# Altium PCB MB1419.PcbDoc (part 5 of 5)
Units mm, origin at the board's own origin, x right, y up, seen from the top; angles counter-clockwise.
Board outline 31 x 41 mm, 8 copper layers (Top Layer, Signal Layer 1, Signal Layer 2, Signal Layer 3, Signal Layer 4, Signal Layer 5, Signal Layer 6, Bottom Layer), stack 1.536 mm thick; 212 components, 125 nets, 637 pads, 2170 vias.

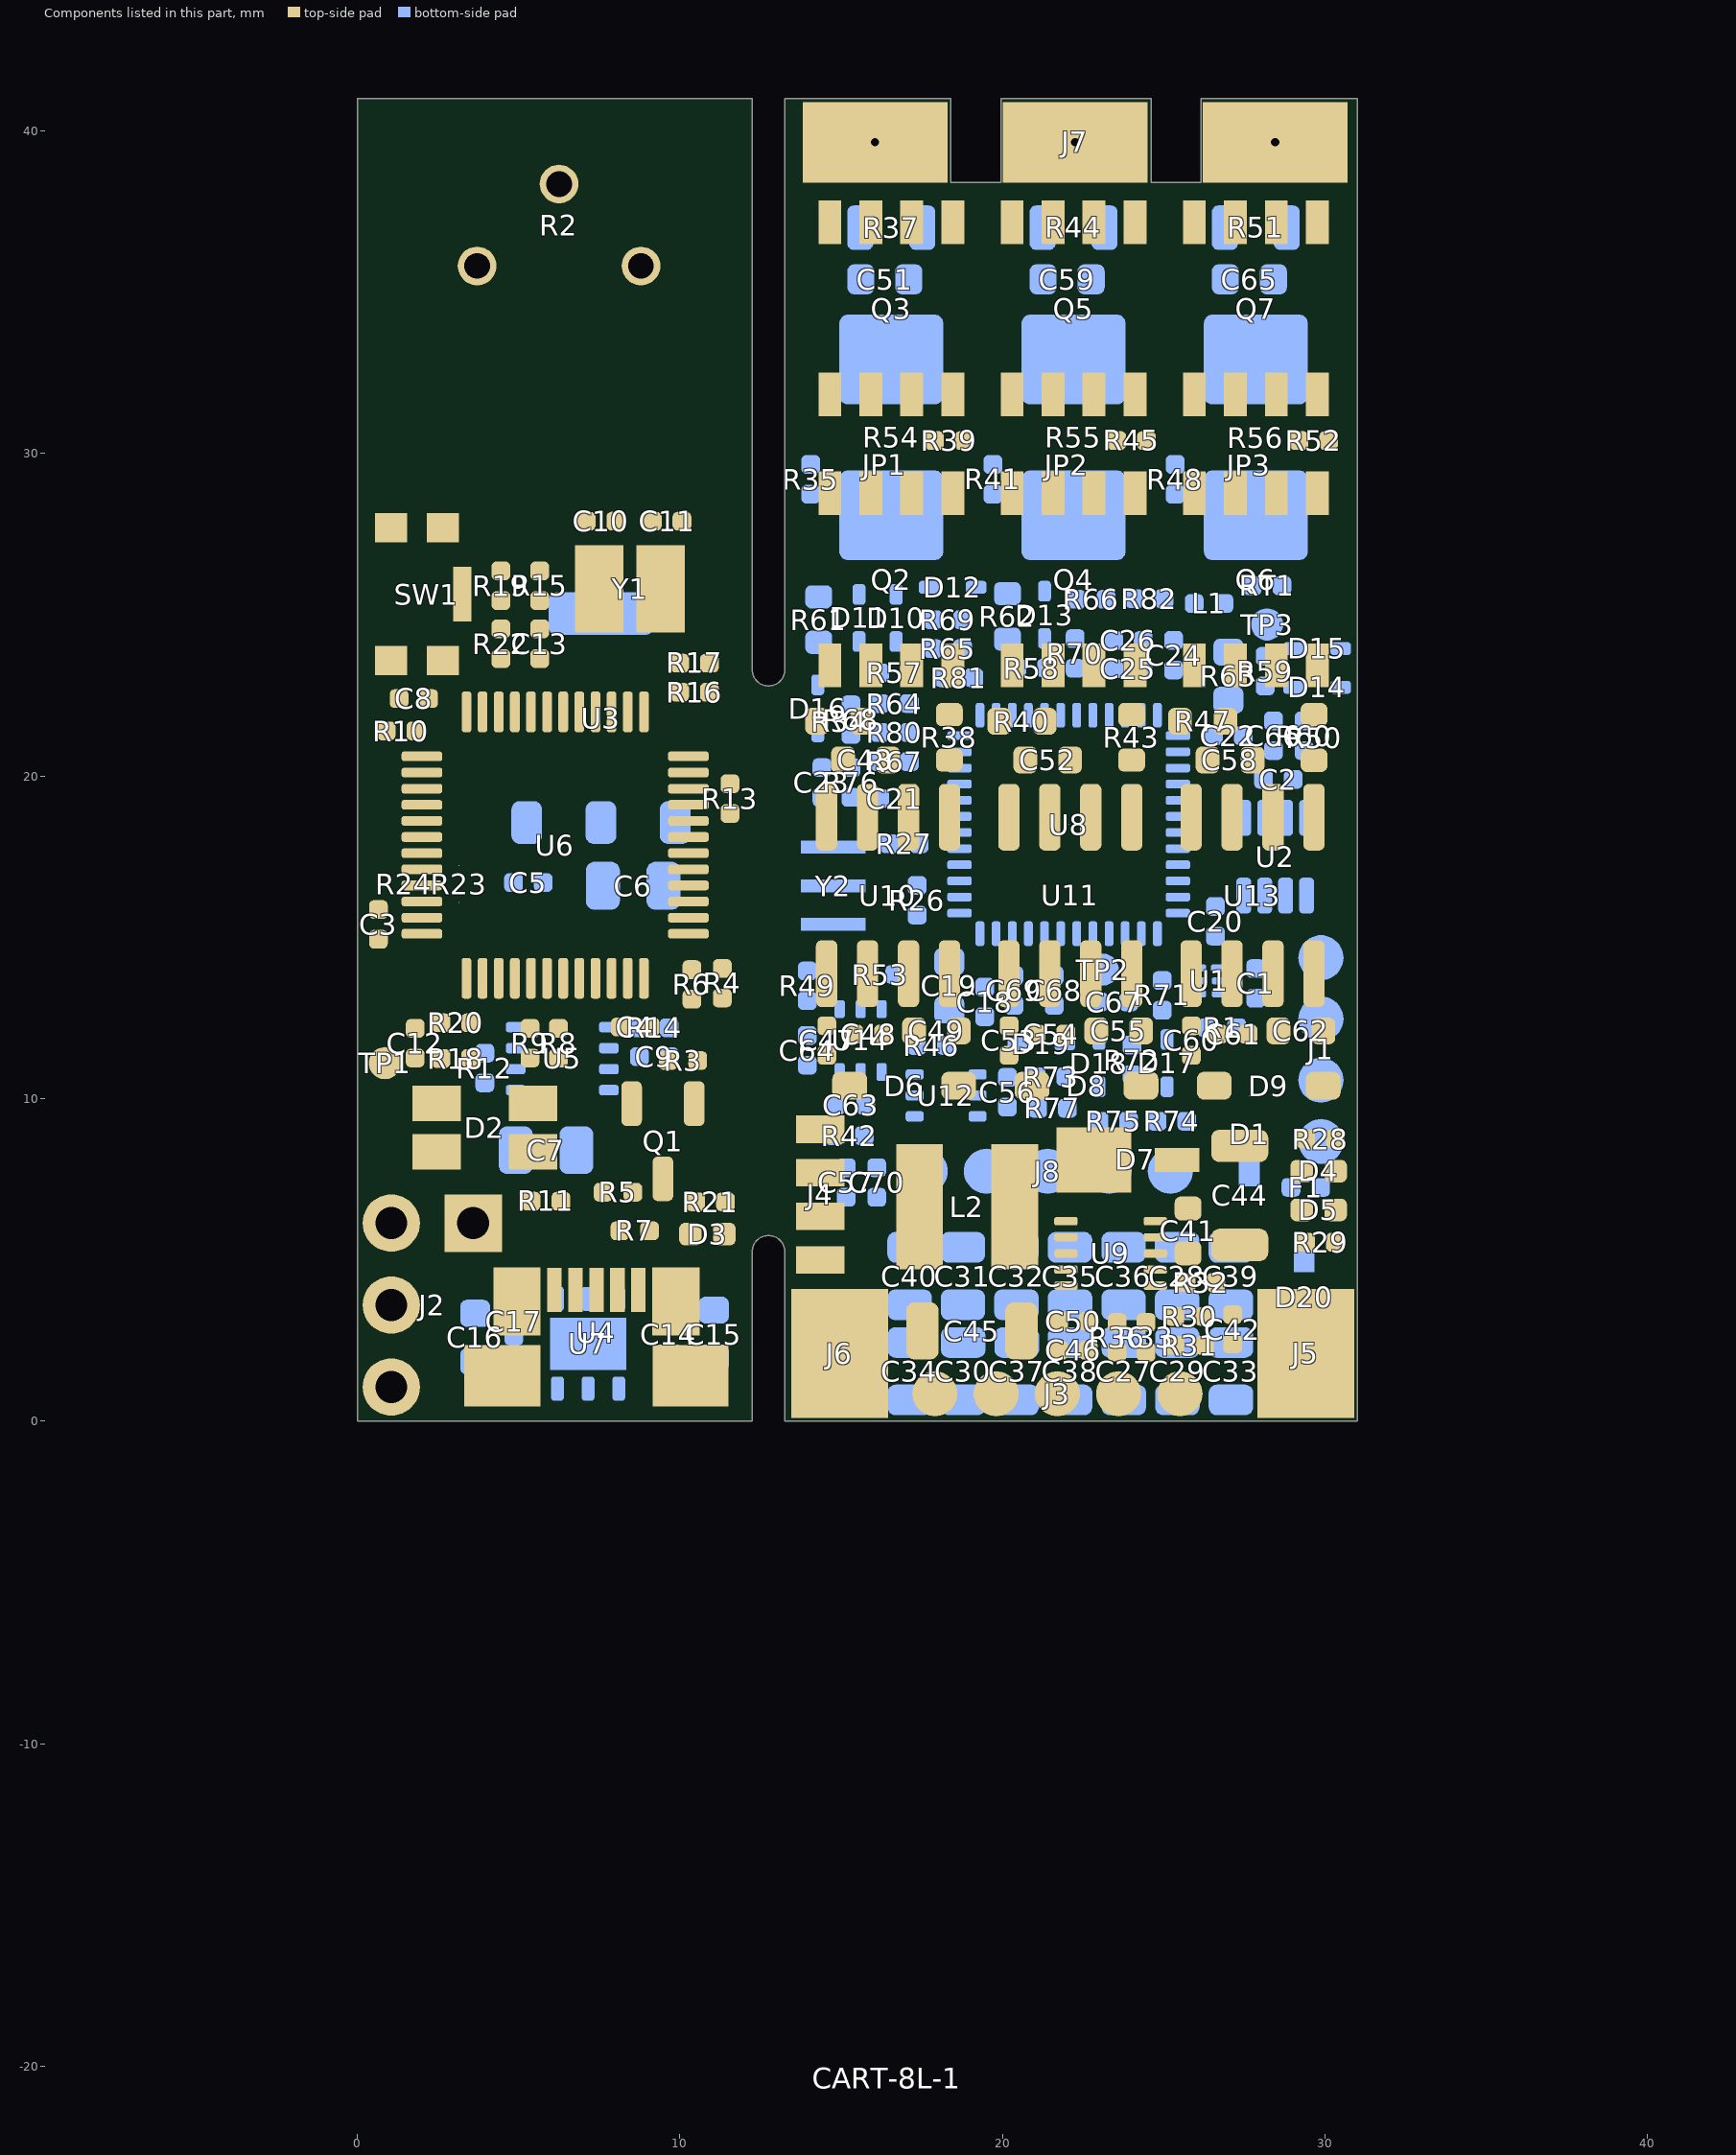
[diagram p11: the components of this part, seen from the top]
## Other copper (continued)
Signal Layer 4:
  pour cut-out: 29.307,11.205 29.271,11.384 29.17,11.535 29.019,11.636 28.841,11.671 28.663,11.636 28.512,11.535 28.411,11.384 28.376,11.205 28.411,11.027 28.512,10.876 28.663,10.775 28.841,10.74 29.019,10.775 29.17,10.876 29.271,11.027 29.307,11.205
  pour cut-out: 24.489,17.45 24.452,17.637 24.346,17.796 24.187,17.902 24,17.939 23.813,17.902 23.654,17.796 23.548,17.637 23.511,17.45 23.548,17.263 23.654,17.104 23.813,16.998 24,16.961 24.187,16.998 24.346,17.104 24.452,17.263 24.489,17.45
  pour cut-out: 30.639,22.55 30.602,22.737 30.496,22.896 30.337,23.002 30.15,23.039 29.963,23.002 29.804,22.896 29.698,22.737 29.661,22.55 29.698,22.363 29.804,22.204 29.963,22.098 30.15,22.061 30.337,22.098 30.496,22.204 30.602,22.363 30.639,22.55
  pour cut-out: 30.116,17.45 30.08,17.628 29.979,17.779 29.828,17.88 29.65,17.916 29.472,17.88 29.321,17.779 29.22,17.628 29.184,17.45 29.22,17.272 29.321,17.121 29.472,17.02 29.65,16.984 29.828,17.02 29.979,17.121 30.08,17.272 30.116,17.45
  pour cut-out: 29.789,5.55 29.752,5.737 29.646,5.896 29.487,6.002 29.3,6.039 29.113,6.002 28.954,5.896 28.848,5.737 28.811,5.55 28.848,5.363 28.954,5.204 29.113,5.098 29.3,5.061 29.487,5.098 29.646,5.204 29.752,5.363 29.789,5.55
  pour cut-out: 28.546,18.539 28.509,18.726 28.403,18.884 28.244,18.99 28.057,19.028 27.87,18.99 27.711,18.884 27.605,18.726 27.568,18.539 27.605,18.351 27.711,18.193 27.87,18.087 28.057,18.05 28.244,18.087 28.403,18.193 28.509,18.351 28.546,18.539
  pour cut-out: 28.239,21.766 28.202,21.954 28.096,22.112 27.937,22.218 27.75,22.255 27.563,22.218 27.404,22.112 27.298,21.954 27.261,21.766 27.298,21.579 27.404,21.421 27.563,21.315 27.75,21.277 27.937,21.315 28.096,21.421 28.202,21.579 28.239,21.766
  pour cut-out: 26.939,24.05 26.902,24.237 26.796,24.396 26.637,24.502 26.45,24.539 26.263,24.502 26.104,24.396 25.998,24.237 25.961,24.05 25.998,23.863 26.104,23.704 26.263,23.598 26.45,23.561 26.637,23.598 26.796,23.704 26.902,23.863 26.939,24.05
  pour cut-out: 27.016,11.3 26.98,11.478 26.879,11.629 26.728,11.73 26.55,11.766 26.372,11.73 26.221,11.629 26.12,11.478 26.084,11.3 26.12,11.122 26.221,10.971 26.372,10.87 26.55,10.834 26.728,10.87 26.879,10.971 26.98,11.122 27.016,11.3
  pour cut-out: 26.299,3.74 26.262,3.927 26.156,4.086 25.997,4.192 25.81,4.229 25.623,4.192 25.464,4.086 25.358,3.927 25.321,3.74 25.358,3.553 25.464,3.394 25.623,3.288 25.81,3.251 25.997,3.288 26.156,3.394 26.262,3.553 26.299,3.74
  pour cut-out: 25.989,22.15 25.952,22.337 25.846,22.496 25.687,22.602 25.5,22.639 25.313,22.602 25.154,22.496 25.048,22.337 25.011,22.15 25.048,21.963 25.154,21.804 25.313,21.698 25.5,21.661 25.687,21.698 25.846,21.804 25.952,21.963 25.989,22.15
  pour cut-out: 24.839,22.25 24.802,22.437 24.696,22.596 24.537,22.702 24.35,22.739 24.163,22.702 24.004,22.596 23.898,22.437 23.861,22.25 23.898,22.063 24.004,21.904 24.163,21.798 24.35,21.761 24.537,21.798 24.696,21.904 24.802,22.063 24.839,22.25
  pour cut-out: 23.889,13.5 23.852,13.687 23.746,13.846 23.587,13.952 23.4,13.989 23.213,13.952 23.054,13.846 22.948,13.687 22.911,13.5 22.948,13.313 23.054,13.154 23.213,13.048 23.4,13.011 23.587,13.048 23.746,13.154 23.852,13.313 23.889,13.5
  pour cut-out: 20.834,25.055 20.797,25.242 20.691,25.401 20.532,25.507 20.345,25.544 20.158,25.507 19.999,25.401 19.893,25.242 19.856,25.055 19.893,24.868 19.999,24.709 20.158,24.603 20.345,24.566 20.532,24.603 20.691,24.709 20.797,24.868 20.834,25.055
  pour cut-out: 20.289,14.3 20.252,14.487 20.146,14.646 19.987,14.752 19.8,14.789 19.613,14.752 19.454,14.646 19.348,14.487 19.311,14.3 19.348,14.113 19.454,13.954 19.613,13.848 19.8,13.811 19.987,13.848 20.146,13.954 20.252,14.113 20.289,14.3
  pour cut-out: 20.316,11.05 20.28,11.228 20.179,11.379 20.028,11.48 19.85,11.516 19.672,11.48 19.521,11.379 19.42,11.228 19.384,11.05 19.42,10.872 19.521,10.721 19.672,10.62 19.85,10.584 20.028,10.62 20.179,10.721 20.28,10.872 20.316,11.05
  pour cut-out: 19.216,11.6 19.18,11.778 19.079,11.929 18.928,12.03 18.75,12.066 18.572,12.03 18.421,11.929 18.32,11.778 18.284,11.6 18.32,11.422 18.421,11.271 18.572,11.17 18.75,11.134 18.928,11.17 19.079,11.271 19.18,11.422 19.216,11.6
  pour cut-out: 18.666,17.25 18.63,17.428 18.529,17.579 18.378,17.68 18.2,17.716 18.022,17.68 17.871,17.579 17.77,17.428 17.734,17.25 17.77,17.072 17.871,16.921 18.022,16.82 18.2,16.784 18.378,16.82 18.529,16.921 18.63,17.072 18.666,17.25
  pour cut-out: 15.039,25.05 15.002,25.237 14.896,25.396 14.737,25.502 14.55,25.539 14.363,25.502 14.204,25.396 14.098,25.237 14.061,25.05 14.098,24.863 14.204,24.704 14.363,24.598 14.55,24.561 14.737,24.598 14.896,24.704 15.002,24.863 15.039,25.05
  pour cut-out: 14.739,22.2 14.702,22.387 14.596,22.546 14.437,22.652 14.25,22.689 14.063,22.652 13.904,22.546 13.798,22.387 13.761,22.2 13.798,22.013 13.904,21.854 14.063,21.748 14.25,21.711 14.437,21.748 14.596,21.854 14.702,22.013 14.739,22.2
  pour cut-out: 10.989,6.65 10.952,6.837 10.846,6.996 10.687,7.102 10.5,7.139 10.313,7.102 10.154,6.996 10.048,6.837 10.011,6.65 10.048,6.463 10.154,6.304 10.313,6.198 10.5,6.161 10.687,6.198 10.846,6.304 10.952,6.463 10.989,6.65
  pour cut-out: 9.539,20.55 9.502,20.737 9.396,20.896 9.237,21.002 9.05,21.039 8.863,21.002 8.704,20.896 8.598,20.737 8.561,20.55 8.598,20.363 8.704,20.204 8.863,20.098 9.05,20.061 9.237,20.098 9.396,20.204 9.502,20.363 9.539,20.55
  pour cut-out: 9.911,14.581 9.874,14.768 9.768,14.926 9.609,15.032 9.422,15.07 9.235,15.032 9.076,14.926 8.97,14.768 8.933,14.581 8.97,14.393 9.076,14.235 9.235,14.129 9.422,14.092 9.609,14.129 9.768,14.235 9.874,14.393 9.911,14.581
  pour cut-out: 9.698,35.815 9.667,36.05 9.576,36.269 9.432,36.457 9.244,36.601 9.025,36.692 8.79,36.723 8.555,36.692 8.336,36.601 8.148,36.457 8.004,36.269 7.913,36.05 7.882,35.815 7.913,35.58 8.004,35.361 8.148,35.173 8.336,35.029 8.555,34.938 8.79,34.907 9.025,34.938 9.244,35.029 9.432,35.173 9.576,35.361 9.667,35.58 9.698,35.815
  pour cut-out: 8.089,12.55 8.052,12.737 7.946,12.896 7.787,13.002 7.6,13.039 7.413,13.002 7.254,12.896 7.148,12.737 7.111,12.55 7.148,12.363 7.254,12.204 7.413,12.098 7.6,12.061 7.787,12.098 7.946,12.204 8.052,12.363 8.089,12.55
  pour cut-out: 7.173,15.11 7.135,15.297 7.029,15.456 6.871,15.562 6.684,15.599 6.496,15.562 6.338,15.456 6.232,15.297 6.195,15.11 6.232,14.923 6.338,14.764 6.496,14.658 6.684,14.621 6.871,14.658 7.029,14.764 7.135,14.923 7.173,15.11
  pour cut-out: 7.158,38.355 7.127,38.59 7.036,38.809 6.892,38.997 6.704,39.141 6.485,39.232 6.25,39.263 6.015,39.232 5.796,39.141 5.608,38.997 5.464,38.809 5.373,38.59 5.342,38.355 5.373,38.12 5.464,37.901 5.608,37.713 5.796,37.569 6.015,37.478 6.25,37.447 6.485,37.478 6.704,37.569 6.892,37.713 7.036,37.901 7.127,38.12 7.158,38.355
  pour cut-out: 4.689,11.8 4.652,11.987 4.546,12.146 4.387,12.252 4.2,12.289 4.013,12.252 3.854,12.146 3.748,11.987 3.711,11.8 3.748,11.613 3.854,11.454 4.013,11.348 4.2,11.311 4.387,11.348 4.546,11.454 4.652,11.613 4.689,11.8
  pour cut-out: 4.544,35.815 4.516,36.031 4.433,36.232 4.3,36.405 4.127,36.538 3.926,36.621 3.71,36.649 3.494,36.621 3.293,36.538 3.12,36.405 2.987,36.232 2.904,36.031 2.876,35.815 2.904,35.599 2.987,35.398 3.12,35.225 3.293,35.092 3.494,35.009 3.71,34.981 3.926,35.009 4.127,35.092 4.3,35.225 4.433,35.398 4.516,35.599 4.544,35.815
  pour cut-out: 3.739,20.3 3.702,20.487 3.596,20.646 3.437,20.752 3.25,20.789 3.063,20.752 2.904,20.646 2.798,20.487 2.761,20.3 2.798,20.113 2.904,19.954 3.063,19.848 3.25,19.811 3.437,19.848 3.596,19.954 3.702,20.113 3.739,20.3
  pour cut-out: 1.339,21.884 1.302,22.071 1.196,22.229 1.037,22.335 0.85,22.373 0.663,22.335 0.504,22.229 0.398,22.071 0.361,21.884 0.398,21.696 0.504,21.538 0.663,21.432 0.85,21.395 1.037,21.432 1.196,21.538 1.302,21.696 1.339,21.884
  pour cut-out: 1.339,20.6 1.302,20.787 1.196,20.946 1.037,21.052 0.85,21.089 0.663,21.052 0.504,20.946 0.398,20.787 0.361,20.6 0.398,20.413 0.504,20.254 0.663,20.148 0.85,20.111 1.037,20.148 1.196,20.254 1.302,20.413 1.339,20.6
  pour cut-out: 1.939,14.3 1.902,14.487 1.796,14.646 1.637,14.752 1.45,14.789 1.263,14.752 1.104,14.646 0.998,14.487 0.961,14.3 0.998,14.113 1.104,13.954 1.263,13.848 1.45,13.811 1.637,13.848 1.796,13.954 1.902,14.113 1.939,14.3
  pour cut-out: 3.089,14.501 3.052,14.688 2.946,14.846 2.787,14.952 2.6,14.99 2.413,14.952 2.254,14.846 2.148,14.688 2.111,14.501 2.148,14.313 2.254,14.155 2.413,14.049 2.6,14.012 2.787,14.049 2.946,14.155 3.052,14.313 3.089,14.501
  pour cut-out: 23.633,11.626 ccw(c24.09,11.626) 24.09,11.169 ccw(c24.09,11.626) 24.547,11.626 ccw(c24.09,11.626) 24.09,12.083 ccw(c24.09,11.626)
  pour cut-out: 14.833,12 ccw(c15.29,12) 15.29,11.543 ccw(c15.29,12) 15.747,12 ccw(c15.29,12) 15.29,12.457 ccw(c15.29,12)
  text "5" at 0.575,34.175 h1.3 r270
Signal Layer 5:
  pour cut-out: 14.739,22.2 14.702,22.387 14.596,22.546 14.437,22.652 14.25,22.689 14.063,22.652 13.904,22.546 13.798,22.387 13.761,22.2 13.798,22.013 13.904,21.854 14.063,21.748 14.25,21.711 14.437,21.748 14.596,21.854 14.702,22.013 14.739,22.2
  pour cut-out: 15.439,23.2 15.402,23.387 15.296,23.546 15.137,23.652 14.95,23.689 14.763,23.652 14.604,23.546 14.498,23.387 14.461,23.2 14.498,23.013 14.604,22.854 14.763,22.748 14.95,22.711 15.137,22.748 15.296,22.854 15.402,23.013 15.439,23.2
  pour cut-out: 16.963,21.7 16.926,21.887 16.82,22.046 16.662,22.152 16.474,22.189 16.287,22.152 16.129,22.046 16.023,21.887 15.985,21.7 16.023,21.513 16.129,21.354 16.287,21.248 16.474,21.211 16.662,21.248 16.82,21.354 16.926,21.513 16.963,21.7
  pour cut-out: 18.689,17.25 18.652,17.437 18.546,17.596 18.387,17.702 18.2,17.739 18.013,17.702 17.854,17.596 17.748,17.437 17.711,17.25 17.748,17.063 17.854,16.904 18.013,16.798 18.2,16.761 18.387,16.798 18.546,16.904 18.652,17.063 18.689,17.25
  pour cut-out: 19.239,11.6 19.202,11.787 19.096,11.946 18.937,12.052 18.75,12.089 18.563,12.052 18.404,11.946 18.298,11.787 18.261,11.6 18.298,11.413 18.404,11.254 18.563,11.148 18.75,11.111 18.937,11.148 19.096,11.254 19.202,11.413 19.239,11.6
  pour cut-out: 20.714,12.275 20.677,12.462 20.571,12.621 20.412,12.727 20.225,12.764 20.038,12.727 19.879,12.621 19.773,12.462 19.736,12.275 19.773,12.088 19.879,11.929 20.038,11.823 20.225,11.786 20.412,11.823 20.571,11.929 20.677,12.088 20.714,12.275
  pour cut-out: 24.839,22.25 24.802,22.437 24.696,22.596 24.537,22.702 24.35,22.739 24.163,22.702 24.004,22.596 23.898,22.437 23.861,22.25 23.898,22.063 24.004,21.904 24.163,21.798 24.35,21.761 24.537,21.798 24.696,21.904 24.802,22.063 24.839,22.25
  pour cut-out: 25.989,22.15 25.952,22.337 25.846,22.496 25.687,22.602 25.5,22.639 25.313,22.602 25.154,22.496 25.048,22.337 25.011,22.15 25.048,21.963 25.154,21.804 25.313,21.698 25.5,21.661 25.687,21.698 25.846,21.804 25.952,21.963 25.989,22.15
  pour cut-out: 26.289,12.3 26.252,12.487 26.146,12.646 25.987,12.752 25.8,12.789 25.613,12.752 25.454,12.646 25.348,12.487 25.311,12.3 25.348,12.113 25.454,11.954 25.613,11.848 25.8,11.811 25.987,11.848 26.146,11.954 26.252,12.113 26.289,12.3
  pour cut-out: 27.039,11.3 27.002,11.487 26.896,11.646 26.737,11.752 26.55,11.789 26.363,11.752 26.204,11.646 26.098,11.487 26.061,11.3 26.098,11.113 26.204,10.954 26.363,10.848 26.55,10.811 26.737,10.848 26.896,10.954 27.002,11.113 27.039,11.3
  pour cut-out: 28.239,21.766 28.202,21.954 28.096,22.112 27.937,22.218 27.75,22.255 27.563,22.218 27.404,22.112 27.298,21.954 27.261,21.766 27.298,21.579 27.404,21.421 27.563,21.315 27.75,21.277 27.937,21.315 28.096,21.421 28.202,21.579 28.239,21.766
  pour cut-out: 28.939,8.75 28.902,8.937 28.796,9.096 28.637,9.202 28.45,9.239 28.263,9.202 28.104,9.096 27.998,8.937 27.961,8.75 27.998,8.563 28.104,8.404 28.263,8.298 28.45,8.261 28.637,8.298 28.796,8.404 28.902,8.563 28.939,8.75
  pour cut-out: 30.139,17.45 30.102,17.637 29.996,17.796 29.837,17.902 29.65,17.939 29.463,17.902 29.304,17.796 29.198,17.637 29.161,17.45 29.198,17.263 29.304,17.104 29.463,16.998 29.65,16.961 29.837,16.998 29.996,17.104 30.102,17.263 30.139,17.45
  pour cut-out: 30.639,22.55 30.602,22.737 30.496,22.896 30.337,23.002 30.15,23.039 29.963,23.002 29.804,22.896 29.698,22.737 29.661,22.55 29.698,22.363 29.804,22.204 29.963,22.098 30.15,22.061 30.337,22.098 30.496,22.204 30.602,22.363 30.639,22.55
  pour cut-out: 11.839,27.9 11.802,28.087 11.696,28.246 11.537,28.352 11.35,28.389 11.163,28.352 11.004,28.246 10.898,28.087 10.861,27.9 10.898,27.713 11.004,27.554 11.163,27.448 11.35,27.411 11.537,27.448 11.696,27.554 11.802,27.713 11.839,27.9
  pour cut-out: 11.839,24.75 11.802,24.937 11.696,25.096 11.537,25.202 11.35,25.239 11.163,25.202 11.004,25.096 10.898,24.937 10.861,24.75 10.898,24.563 11.004,24.404 11.163,24.298 11.35,24.261 11.537,24.298 11.696,24.404 11.802,24.563 11.839,24.75
  pour cut-out: 9.539,20.55 9.502,20.737 9.396,20.896 9.237,21.002 9.05,21.039 8.863,21.002 8.704,20.896 8.598,20.737 8.561,20.55 8.598,20.363 8.704,20.204 8.863,20.098 9.05,20.061 9.237,20.098 9.396,20.204 9.502,20.363 9.539,20.55
  pour cut-out: 9.624,35.815 9.596,36.031 9.513,36.232 9.38,36.405 9.207,36.538 9.006,36.621 8.79,36.649 8.574,36.621 8.373,36.538 8.2,36.405 8.067,36.232 7.984,36.031 7.956,35.815 7.984,35.599 8.067,35.398 8.2,35.225 8.373,35.092 8.574,35.009 8.79,34.981 9.006,35.009 9.207,35.092 9.38,35.225 9.513,35.398 9.596,35.599 9.624,35.815
  pour cut-out: 9.089,28.75 9.052,28.937 8.946,29.096 8.787,29.202 8.6,29.239 8.413,29.202 8.254,29.096 8.148,28.937 8.111,28.75 8.148,28.563 8.254,28.404 8.413,28.298 8.6,28.261 8.787,28.298 8.946,28.404 9.052,28.563 9.089,28.75
  pour cut-out: 8.089,12.55 8.052,12.737 7.946,12.896 7.787,13.002 7.6,13.039 7.413,13.002 7.254,12.896 7.148,12.737 7.111,12.55 7.148,12.363 7.254,12.204 7.413,12.098 7.6,12.061 7.787,12.098 7.946,12.204 8.052,12.363 8.089,12.55
  pour cut-out: 7.158,38.355 7.127,38.59 7.036,38.809 6.892,38.997 6.704,39.141 6.485,39.232 6.25,39.263 6.015,39.232 5.796,39.141 5.608,38.997 5.464,38.809 5.373,38.59 5.342,38.355 5.373,38.12 5.464,37.901 5.608,37.713 5.796,37.569 6.015,37.478 6.25,37.447 6.485,37.478 6.704,37.569 6.892,37.713 7.036,37.901 7.127,38.12 7.158,38.355
  pour cut-out: 6.489,17.45 6.452,17.637 6.346,17.796 6.187,17.902 6,17.939 5.813,17.902 5.654,17.796 5.548,17.637 5.511,17.45 5.548,17.263 5.654,17.104 5.813,16.998 6,16.961 6.187,16.998 6.346,17.104 6.452,17.263 6.489,17.45
  pour cut-out: 4.689,11.8 4.652,11.987 4.546,12.146 4.387,12.252 4.2,12.289 4.013,12.252 3.854,12.146 3.748,11.987 3.711,11.8 3.748,11.613 3.854,11.454 4.013,11.348 4.2,11.311 4.387,11.348 4.546,11.454 4.652,11.613 4.689,11.8
  pour cut-out: 4.618,35.815 4.587,36.05 4.496,36.269 4.352,36.457 4.164,36.601 3.945,36.692 3.71,36.723 3.475,36.692 3.256,36.601 3.068,36.457 2.924,36.269 2.833,36.05 2.802,35.815 2.833,35.58 2.924,35.361 3.068,35.173 3.256,35.029 3.475,34.938 3.71,34.907 3.945,34.938 4.164,35.029 4.352,35.173 4.496,35.361 4.587,35.58 4.618,35.815
  pour cut-out: 3.739,20.3 3.702,20.487 3.596,20.646 3.437,20.752 3.25,20.789 3.063,20.752 2.904,20.646 2.798,20.487 2.761,20.3 2.798,20.113 2.904,19.954 3.063,19.848 3.25,19.811 3.437,19.848 3.596,19.954 3.702,20.113 3.739,20.3
  pour cut-out: 3.439,1.1 3.402,1.287 3.296,1.446 3.137,1.552 2.95,1.589 2.763,1.552 2.604,1.446 2.498,1.287 2.461,1.1 2.498,0.913 2.604,0.754 2.763,0.648 2.95,0.611 3.137,0.648 3.296,0.754 3.402,0.913 3.439,1.1
  pour cut-out: 1.739,9.85 1.702,10.037 1.596,10.196 1.437,10.302 1.25,10.339 1.063,10.302 0.904,10.196 0.798,10.037 0.761,9.85 0.798,9.663 0.904,9.504 1.063,9.398 1.25,9.361 1.437,9.398 1.596,9.504 1.702,9.663 1.739,9.85
  pour cut-out: 1.339,21.884 1.302,22.071 1.196,22.229 1.037,22.335 0.85,22.373 0.663,22.335 0.504,22.229 0.398,22.071 0.361,21.884 0.398,21.696 0.504,21.538 0.663,21.432 0.85,21.395 1.037,21.432 1.196,21.538 1.302,21.696 1.339,21.884
  pour cut-out: 1.339,20.6 1.302,20.787 1.196,20.946 1.037,21.052 0.85,21.089 0.663,21.052 0.504,20.946 0.398,20.787 0.361,20.6 0.398,20.413 0.504,20.254 0.663,20.148 0.85,20.111 1.037,20.148 1.196,20.254 1.302,20.413 1.339,20.6
  pour cut-out: 1.339,12.9 1.302,13.087 1.196,13.246 1.037,13.352 0.85,13.389 0.663,13.352 0.504,13.246 0.398,13.087 0.361,12.9 0.398,12.713 0.504,12.554 0.663,12.448 0.85,12.411 1.037,12.448 1.196,12.554 1.302,12.713 1.339,12.9
  pour cut-out: 1.939,14.3 1.902,14.487 1.796,14.646 1.637,14.752 1.45,14.789 1.263,14.752 1.104,14.646 0.998,14.487 0.961,14.3 0.998,14.113 1.104,13.954 1.263,13.848 1.45,13.811 1.637,13.848 1.796,13.954 1.902,14.113 1.939,14.3
  pour cut-out: 3.089,14.501 3.052,14.688 2.946,14.846 2.787,14.952 2.6,14.99 2.413,14.952 2.254,14.846 2.148,14.688 2.111,14.501 2.148,14.313 2.254,14.155 2.413,14.049 2.6,14.012 2.787,14.049 2.946,14.155 3.052,14.313 3.089,14.501
  text "6" at 0.575,33.3 h1.3 r270
Signal Layer 6:
  pour cut-out: 14.616,25.555 14.592,25.676 14.524,25.779 14.421,25.847 14.3,25.871 14.179,25.847 14.076,25.779 14.008,25.676 13.984,25.555 14.008,25.434 14.076,25.331 14.179,25.263 14.3,25.239 14.421,25.263 14.524,25.331 14.592,25.434 14.616,25.555
  pour cut-out: 16.506,20.45 16.482,20.571 16.414,20.674 16.311,20.742 16.19,20.766 16.069,20.742 15.966,20.674 15.898,20.571 15.874,20.45 15.898,20.329 15.966,20.226 16.069,20.158 16.19,20.134 16.311,20.158 16.414,20.226 16.482,20.329 16.506,20.45
  pour cut-out: 16.506,22.25 16.482,22.371 16.414,22.474 16.311,22.542 16.19,22.566 16.069,22.542 15.966,22.474 15.898,22.371 15.874,22.25 15.898,22.129 15.966,22.026 16.069,21.958 16.19,21.934 16.311,21.958 16.414,22.026 16.482,22.129 16.506,22.25
  pour cut-out: 17.866,13.8 17.842,13.921 17.774,14.024 17.671,14.092 17.55,14.116 17.429,14.092 17.326,14.024 17.258,13.921 17.234,13.8 17.258,13.679 17.326,13.576 17.429,13.508 17.55,13.484 17.671,13.508 17.774,13.576 17.842,13.679 17.866,13.8
  pour cut-out: 18.316,16.25 18.292,16.371 18.224,16.474 18.121,16.542 18,16.566 17.879,16.542 17.776,16.474 17.708,16.371 17.684,16.25 17.708,16.129 17.776,16.026 17.879,15.958 18,15.934 18.121,15.958 18.224,16.026 18.292,16.129 18.316,16.25
  pour cut-out: 18.356,23.79 18.332,23.911 18.264,24.014 18.161,24.082 18.04,24.106 17.919,24.082 17.816,24.014 17.748,23.911 17.724,23.79 17.748,23.669 17.816,23.566 17.919,23.498 18.04,23.474 18.161,23.498 18.264,23.566 18.332,23.669 18.356,23.79
  pour cut-out: 18.356,25.25 18.332,25.371 18.264,25.474 18.161,25.542 18.04,25.566 17.919,25.542 17.816,25.474 17.748,25.371 17.724,25.25 17.748,25.129 17.816,25.026 17.919,24.958 18.04,24.934 18.161,24.958 18.264,25.026 18.332,25.129 18.356,25.25
  pour cut-out: 18.716,20.75 18.692,20.871 18.624,20.974 18.521,21.042 18.4,21.066 18.279,21.042 18.176,20.974 18.108,20.871 18.084,20.75 18.108,20.629 18.176,20.526 18.279,20.458 18.4,20.434 18.521,20.458 18.624,20.526 18.692,20.629 18.716,20.75
  pour cut-out: 19.316,14.195 19.292,14.316 19.224,14.419 19.121,14.487 19,14.511 18.879,14.487 18.776,14.419 18.708,14.316 18.684,14.195 18.708,14.074 18.776,13.971 18.879,13.903 19,13.879 19.121,13.903 19.224,13.971 19.292,14.074 19.316,14.195
  pour cut-out: 19.331,21.885 19.307,22.006 19.239,22.109 19.136,22.177 19.015,22.201 18.894,22.177 18.791,22.109 18.723,22.006 18.699,21.885 18.723,21.764 18.791,21.661 18.894,21.593 19.015,21.569 19.136,21.593 19.239,21.661 19.307,21.764 19.331,21.885
  pour cut-out: 20.116,14.65 20.092,14.771 20.024,14.874 19.921,14.942 19.8,14.966 19.679,14.942 19.576,14.874 19.508,14.771 19.484,14.65 19.508,14.529 19.576,14.426 19.679,14.358 19.8,14.334 19.921,14.358 20.024,14.426 20.092,14.529 20.116,14.65
  pour cut-out: 20.786,11.28 20.762,11.401 20.694,11.504 20.591,11.572 20.47,11.596 20.349,11.572 20.246,11.504 20.178,11.401 20.154,11.28 20.178,11.159 20.246,11.056 20.349,10.988 20.47,10.964 20.591,10.988 20.694,11.056 20.762,11.159 20.786,11.28
  pour cut-out: 22.566,24.26 22.542,24.381 22.474,24.484 22.371,24.552 22.25,24.576 22.129,24.552 22.026,24.484 21.958,24.381 21.934,24.26 21.958,24.139 22.026,24.036 22.129,23.968 22.25,23.944 22.371,23.968 22.474,24.036 22.542,24.139 22.566,24.26
  pour cut-out: 23.306,10.91 23.282,11.031 23.214,11.134 23.111,11.202 22.99,11.226 22.869,11.202 22.766,11.134 22.698,11.031 22.674,10.91 22.698,10.789 22.766,10.686 22.869,10.618 22.99,10.594 23.111,10.618 23.214,10.686 23.282,10.789 23.306,10.91
  pour cut-out: 24.258,13.662 24.234,13.783 24.165,13.885 24.063,13.954 23.941,13.978 23.82,13.954 23.718,13.885 23.649,13.783 23.625,13.662 23.649,13.541 23.718,13.438 23.82,13.369 23.941,13.345 24.063,13.369 24.165,13.438 24.234,13.541 24.258,13.662
  pour cut-out: 25.416,10.95 25.392,11.071 25.324,11.174 25.221,11.242 25.1,11.266 24.979,11.242 24.876,11.174 24.808,11.071 24.784,10.95 24.808,10.829 24.876,10.726 24.979,10.658 25.1,10.634 25.221,10.658 25.324,10.726 25.392,10.829 25.416,10.95
  pour cut-out: 25.751,15.465 25.727,15.586 25.659,15.689 25.556,15.757 25.435,15.781 25.314,15.757 25.211,15.689 25.143,15.586 25.119,15.465 25.143,15.344 25.211,15.241 25.314,15.173 25.435,15.149 25.556,15.173 25.659,15.241 25.727,15.344 25.751,15.465
  pour cut-out: 26.016,16.75 25.992,16.871 25.924,16.974 25.821,17.042 25.7,17.066 25.579,17.042 25.476,16.974 25.408,16.871 25.384,16.75 25.408,16.629 25.476,16.526 25.579,16.458 25.7,16.434 25.821,16.458 25.924,16.526 25.992,16.629 26.016,16.75
  pour cut-out: 26.916,15.96 26.892,16.081 26.824,16.184 26.721,16.252 26.6,16.276 26.479,16.252 26.376,16.184 26.308,16.081 26.284,15.96 26.308,15.839 26.376,15.736 26.479,15.668 26.6,15.644 26.721,15.668 26.824,15.736 26.892,15.839 26.916,15.96
  pour cut-out: 26.866,21.25 26.842,21.371 26.774,21.474 26.671,21.542 26.55,21.566 26.429,21.542 26.326,21.474 26.258,21.371 26.234,21.25 26.258,21.129 26.326,21.026 26.429,20.958 26.55,20.934 26.671,20.958 26.774,21.026 26.842,21.129 26.866,21.25
  pour cut-out: 27.566,13.25 27.542,13.371 27.474,13.474 27.371,13.542 27.25,13.566 27.129,13.542 27.026,13.474 26.958,13.371 26.934,13.25 26.958,13.129 27.026,13.026 27.129,12.958 27.25,12.934 27.371,12.958 27.474,13.026 27.542,13.129 27.566,13.25
  pour cut-out: 27.771,18.505 27.747,18.626 27.679,18.729 27.576,18.797 27.455,18.821 27.334,18.797 27.231,18.729 27.163,18.626 27.139,18.505 27.163,18.384 27.231,18.281 27.334,18.213 27.455,18.189 27.576,18.213 27.679,18.281 27.747,18.384 27.771,18.505
  pour cut-out: 27.316,24.05 27.292,24.171 27.224,24.274 27.121,24.342 27,24.366 26.879,24.342 26.776,24.274 26.708,24.171 26.684,24.05 26.708,23.929 26.776,23.826 26.879,23.758 27,23.734 27.121,23.758 27.224,23.826 27.292,23.929 27.316,24.05
  pour cut-out: 28.166,14.6 28.142,14.721 28.074,14.824 27.971,14.892 27.85,14.916 27.729,14.892 27.626,14.824 27.558,14.721 27.534,14.6 27.558,14.479 27.626,14.376 27.729,14.308 27.85,14.284 27.971,14.308 28.074,14.376 28.142,14.479 28.166,14.6
  pour cut-out: 28.466,15.6 28.442,15.721 28.374,15.824 28.271,15.892 28.15,15.916 28.029,15.892 27.926,15.824 27.858,15.721 27.834,15.6 27.858,15.479 27.926,15.376 28.029,15.308 28.15,15.284 28.271,15.308 28.374,15.376 28.442,15.479 28.466,15.6
  pour cut-out: 28.016,25.373 27.992,25.494 27.924,25.597 27.821,25.665 27.7,25.689 27.579,25.665 27.476,25.597 27.408,25.494 27.384,25.373 27.408,25.252 27.476,25.149 27.579,25.081 27.7,25.057 27.821,25.081 27.924,25.149 27.992,25.252 28.016,25.373
  pour cut-out: 29.488,9.872 29.464,9.993 29.395,10.095 29.293,10.164 29.172,10.188 29.051,10.164 28.948,10.095 28.88,9.993 28.856,9.872 28.88,9.751 28.948,9.648 29.051,9.58 29.172,9.556 29.293,9.58 29.395,9.648 29.464,9.751 29.488,9.872
  pour cut-out: 29.741,15.503 29.717,15.624 29.649,15.727 29.546,15.795 29.425,15.819 29.304,15.795 29.201,15.727 29.133,15.624 29.109,15.503 29.133,15.382 29.201,15.279 29.304,15.211 29.425,15.187 29.546,15.211 29.649,15.279 29.717,15.382 29.741,15.503
  pour cut-out: 29.803,19.9 29.779,20.021 29.711,20.124 29.608,20.192 29.487,20.216 29.366,20.192 29.263,20.124 29.195,20.021 29.171,19.9 29.195,19.779 29.263,19.676 29.366,19.608 29.487,19.584 29.608,19.608 29.711,19.676 29.779,19.779 29.803,19.9
  pour cut-out: 1.339,20.6 1.302,20.787 1.196,20.946 1.037,21.052 0.85,21.089 0.663,21.052 0.504,20.946 0.398,20.787 0.361,20.6 0.398,20.413 0.504,20.254 0.663,20.148 0.85,20.111 1.037,20.148 1.196,20.254 1.302,20.413 1.339,20.6
  pour cut-out: 1.939,14.3 1.902,14.487 1.796,14.646 1.637,14.752 1.45,14.789 1.263,14.752 1.104,14.646 0.998,14.487 0.961,14.3 0.998,14.113 1.104,13.954 1.263,13.848 1.45,13.811 1.637,13.848 1.796,13.954 1.902,14.113 1.939,14.3
  pour cut-out: 3.089,14.501 3.052,14.688 2.946,14.846 2.787,14.952 2.6,14.99 2.413,14.952 2.254,14.846 2.148,14.688 2.111,14.501 2.148,14.313 2.254,14.155 2.413,14.049 2.6,14.012 2.787,14.049 2.946,14.155 3.052,14.313 3.089,14.501
  pour cut-out: 3.739,20.3 3.702,20.487 3.596,20.646 3.437,20.752 3.25,20.789 3.063,20.752 2.904,20.646 2.798,20.487 2.761,20.3 2.798,20.113 2.904,19.954 3.063,19.848 3.25,19.811 3.437,19.848 3.596,19.954 3.702,20.113 3.739,20.3
  pour cut-out: 4.689,11.8 4.652,11.987 4.546,12.146 4.387,12.252 4.2,12.289 4.013,12.252 3.854,12.146 3.748,11.987 3.711,11.8 3.748,11.613 3.854,11.454 4.013,11.348 4.2,11.311 4.387,11.348 4.546,11.454 4.652,11.613 4.689,11.8
  pour cut-out: 7.158,38.355 7.127,38.59 7.036,38.809 6.892,38.997 6.704,39.141 6.485,39.232 6.25,39.263 6.015,39.232 5.796,39.141 5.608,38.997 5.464,38.809 5.373,38.59 5.342,38.355 5.373,38.12 5.464,37.901 5.608,37.713 5.796,37.569 6.015,37.478 6.25,37.447 6.485,37.478 6.704,37.569 6.892,37.713 7.036,37.901 7.127,38.12 7.158,38.355
  pour cut-out: 9.698,35.815 9.667,36.05 9.576,36.269 9.432,36.457 9.244,36.601 9.025,36.692 8.79,36.723 8.555,36.692 8.336,36.601 8.148,36.457 8.004,36.269 7.913,36.05 7.882,35.815 7.913,35.58 8.004,35.361 8.148,35.173 8.336,35.029 8.555,34.938 8.79,34.907 9.025,34.938 9.244,35.029 9.432,35.173 9.576,35.361 9.667,35.58 9.698,35.815
  pour cut-out: 9.116,1 9.092,1.121 9.024,1.224 8.921,1.292 8.8,1.316 8.679,1.292 8.576,1.224 8.508,1.121 8.484,1 8.508,0.879 8.576,0.776 8.679,0.708 8.8,0.684 8.921,0.708 9.024,0.776 9.092,0.879 9.116,1
  pour cut-out: 9.911,14.581 9.874,14.768 9.768,14.926 9.609,15.032 9.422,15.07 9.235,15.032 9.076,14.926 8.97,14.768 8.933,14.581 8.97,14.393 9.076,14.235 9.235,14.129 9.422,14.092 9.609,14.129 9.768,14.235 9.874,14.393 9.911,14.581
  pour cut-out: 9.539,20.55 9.502,20.737 9.396,20.896 9.237,21.002 9.05,21.039 8.863,21.002 8.704,20.896 8.598,20.737 8.561,20.55 8.598,20.363 8.704,20.204 8.863,20.098 9.05,20.061 9.237,20.098 9.396,20.204 9.502,20.363 9.539,20.55
  pour cut-out: 9.966,4.8 9.942,4.921 9.874,5.024 9.771,5.092 9.65,5.116 9.529,5.092 9.426,5.024 9.358,4.921 9.334,4.8 9.358,4.679 9.426,4.576 9.529,4.508 9.65,4.484 9.771,4.508 9.874,4.576 9.942,4.679 9.966,4.8
  pour cut-out: 10.989,6.65 10.952,6.837 10.846,6.996 10.687,7.102 10.5,7.139 10.313,7.102 10.154,6.996 10.048,6.837 10.011,6.65 10.048,6.463 10.154,6.304 10.313,6.198 10.5,6.161 10.687,6.198 10.846,6.304 10.952,6.463 10.989,6.65
  text "7" at 0.575,32.45 h1.3 r270
Bottom Layer:
  drawing of 284 lines, arcs and shapes, not listed
  text "8" at 0.575,31.6 h1.3 r270
Multi-Layer:
  pour cut-out: 0.4,31.427 1.56,31.427 1.56,38.14 1.55,38.15 0.4,38.15

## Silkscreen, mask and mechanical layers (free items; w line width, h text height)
Top Overlay:
  lines w0.13: 0.2,7.35 4.7,7.35 4.7,5 3.1,5 3.1,0.15 1.8,0.15
  lines w0.15: 13.45,4.35 15.7,4.35 15.7,5.7 16.65,5.7 16.65,9.45 15.65,9.45 15.65,9.75 13.45,9.75 ; 13.45,9.8 14.3,9.8 ; 13.45,9.9 14.3,9.9 ; 13.45,9.95 14.3,9.95 ; 16.8,0.15 16.8,1.75 ; 16.85,0.15 16.85,1.75 ; 16.9,0.15 16.9,1.75 26.45,1.75 26.45,0.15 ; 16.9,1.3 17.35,1.75 17.25,1.75 16.9,1.4 16.9,1.55 17.1,1.75 ; 18.85,0.15 18.85,1.75 ; 20.75,0.15 20.75,1.75 ; 22.65,0.15 22.65,1.75 ; 24.6,0.15 24.6,1.75
  text "SWD" at 16.5,5.775 h1.2 r90
  text "+" at 29.65,4.2 h1.2
  text "SWD" at 2.95,0.3 h1.3 r90
Bottom Overlay:
  drawing of 46 lines, arcs and shapes, not listed
  text "OUT1" at 13.775,34.8 h1.5 r270
  text "OUT2" at 19.6,34.725 h1.5 r270
  text "OUT3" at 29.725,34.675 h1.5 r270
  text "MB1419B" at 24.425,30.7 h1.2 r270
  text "CAN" at 30.075,15.55 h1.3 r270
  text "1" at 30.95,7.5 h1.3 r90
  text "HALL" at 21.86,5.996 h1.3
Top Paste:
  drawing of 215 lines, arcs and shapes, not listed
Bottom Paste:
  drawing of 298 lines, arcs and shapes, not listed
Top Solder:
  circle w0.5: c0.65,39.85 r0.1
  circle w0.5: c0.45,8.9 r0.1
  circle w0.5: c30.55,13.4 r0.1
Bottom Solder:
  drawing of 8 lines, arcs and shapes, not listed
M1-Board Shape:
  lines w0.1: 12.239,41 cw(c12.239,41) 12.239,41 ; 12.239,41 0,41 cw(c0,41) 0,41 0,0 12.239,0 12.239,5.25 cw(c12.745,5.25) 12.745,5.756 cw(c12.745,5.25) 13.25,5.25 13.25,0 31,0 31,41 26.15,41 26.15,38.4 24.607,38.4 24.607,41 19.95,41 19.95,38.4 18.394,38.4 18.394,41 13.25,41 13.25,23.3 cw(c12.744,23.3) 12.744,22.794 cw(c12.744,23.3) 12.239,23.3 12.239,41 ; 12.25,10.556 ccw(c12.728,10.556) 12.728,10.078 12.77,10.078 ccw(c12.77,10.556) 13.248,10.556 13.248,17.923 ccw(c12.772,17.923) 12.772,18.399 12.728,18.399 ccw(c12.728,17.921) 12.25,17.921 12.25,10.556
M2-Board Dimensions:
  lines w0.1: -17.75,17.6 10.3,17.6 12.75,15.15 ; 12.75,15.15 12.75,15.95 11.95,15.15 12.75,15.15
  text "INTERNAL CUTTING" at -17.625,18.075 h2
  text "1mm" at -10.35,15.875 h2
Drill Drawing:
  drawing of 612 lines, arcs and shapes, not listed
  text "MINIMUM PARAMETERS" at -43.549,112.85 h3
  text "PCB : TYPE 4" at 5.348,109.647 h3
  text "DEFAULT" at -47.681,107.098 h3
  text "Symbol" at 52.325,107.047 h1.44
  text "Count" at 57.96,107.047 h1.44
  text "Hole Size" at 63.84,107.047 h1.44
  text "Plated" at 74.199,107.047 h1.44
  text "Hole Type" at 79.146,107.047 h1.44
  text "Drill Layer Pair" at 86.347,107.047 h1.44
  text "Via/Pad" at 102.417,107.047 h1.44
  text "497" at 57.96,104.564 h1.2
  text "0,100mm (3,94mil)" at 63.84,104.564 h1.2
  text "PTH" at 74.199,104.564 h1.2
  text "Round" at 79.146,104.564 h1.2
  text "Signal Layer 1 - Signal Layer 2" at 86.347,104.564 h1.2
  text "Via" at 102.417,104.564 h1.2
  text "ASPECT-RATIO, AXE Z :" at 5.348,104.147 h3
  text "497 Total" at 57.96,102.08 h1.2
  text "TRACKS : 0.200mm           / GAPS : 0.150mm" at -47.725,100.975 h3
  text "6:1 to 8:1 / LEVEL \"B\"" at 5.367,97.399 h3
  text "DRILL SIZE : 0.100mm" at -47.675,97.375 h3
  text "Symbol" at 52.25,96.822 h1.44
  text "Count" at 57.885,96.822 h1.44
  text "Hole Size" at 63.765,96.822 h1.44
  text "Plated" at 74.124,96.822 h1.44
  text "Hole Type" at 79.071,96.822 h1.44
  text "Drill Layer Pair" at 86.272,96.822 h1.44
  text "Via/Pad" at 101.934,96.822 h1.44
  text "499" at 57.885,94.339 h1.2
  text "0,100mm (3,94mil)" at 63.765,94.339 h1.2
  text "PTH" at 74.124,94.339 h1.2
  text "Round" at 79.071,94.339 h1.2
  text "Signal Layer 6 - Bottom Layer" at 86.272,94.339 h1.2
  text "Via" at 101.934,94.339 h1.2
  text "499 Total" at 57.885,91.855 h1.2
  text "PCB SPECIFICATIONS :" at -97.239,90.479 h3
  text "Symbol" at 52.2,87.797 h1.44
  text "Count" at 57.835,87.797 h1.44
  text "Hole Size" at 63.682,87.797 h1.44
  text "Plated" at 74.041,87.797 h1.44
  text "Hole Type" at 78.987,87.797 h1.44
  text "Drill Layer Pair" at 86.189,87.797 h1.44
  text "Via/Pad" at 102.266,87.797 h1.44
  text "A.   MATERIAL :" at -97.239,86.479 h3
  text "FR-4" at -58.739,86.479 h3
  text "TG-170" at -42.239,86.479 h3
  text "X  TG-150" at -23.989,86.479 h3
  text "TG-140" at -7.989,86.479 h3
  text "309" at 57.835,85.314 h1.2
  text "0,100mm (3,94mil)" at 63.682,85.314 h1.2
  text "PTH" at 74.041,85.314 h1.2
  text "Round" at 78.987,85.314 h1.2
  text "Signal Layer 5 - Signal Layer 6" at 86.189,85.314 h1.2
  text "Via" at 102.266,85.314 h1.2
  text "B.   MATERIAL FAMILY :" at -97.239,83.479 h3
  text "N/A" at -58.739,83.479 h3
  text "309 Total" at 57.835,82.83 h1.2
  text "C.   SOLDERMASK COLOR :" at -97.239,80.479 h3
  text "GREEN" at -58.739,80.479 h3
  text "X  BLUE" at -42.239,80.479 h3
  text "RED" at -23.989,80.479 h3
  text "BLACK" at -7.989,80.479 h3
  text "Symbol" at 52.075,78.847 h1.44
  text "Count" at 57.71,78.847 h1.44
  text "Hole Size" at 63.59,78.847 h1.44
  text "Plated" at 73.949,78.847 h1.44
  text "Hole Type" at 78.896,78.847 h1.44
  text "Drill Layer Pair" at 86.097,78.847 h1.44
  text "Via/Pad" at 100.019,78.847 h1.44
  text "D.   SILKSCREEN COLOR :" at -97.239,77.479 h3
  text "X  WHITE" at -58.739,77.479 h3
  text "YELLOW" at -42.239,77.479 h3
  text "BLACK" at -23.989,77.479 h3
  text "Blue ink PANTONE 2955" at -7.989,77.479 h3
  text "484" at 57.71,76.364 h1.2
  text "0,100mm (3,94mil)" at 63.59,76.364 h1.2
  text "PTH" at 73.949,76.364 h1.2
  text "Round" at 78.896,76.364 h1.2
  text "Top Layer - Signal Layer 1" at 86.097,76.364 h1.2
  text "Via" at 100.019,76.364 h1.2
  text "E.   SURFACE FINISH :" at -97.239,74.479 h3
  text "X  ENIG" at -58.739,74.479 h3
  text "IMMERSION SILVER" at -42.239,74.479 h3
  text "IMMERSION TIN" at -7.989,74.479 h3
  text "484 Total" at 57.71,73.88 h1.2
  text "HASL" at -58.739,71.479 h3
  text "HASL (PB-FREE)" at -42.239,71.479 h3
  text "GOLDEN FINGER" at -7.989,71.479 h3
  text "Symbol" at 52,70.022 h1.44
  text "Count" at 57.635,70.022 h1.44
  text "Hole Size" at 63.411,70.022 h1.44
  text "Plated" at 74.367,70.022 h1.44
  text "Hole Type" at 79.313,70.022 h1.44
  text "Drill Layer Pair" at 86.515,70.022 h1.44
  text "Via/Pad" at 102.598,70.022 h1.44
  text "F.   IMPEDANCE CONTROL :" at -97.239,68.479 h3
  text "X  NO" at -58.739,68.479 h3
  text "YES  (SEE IMPEDANCE TABLE FOR DETAIL INFORMATION)" at -42.239,68.479 h3
  text "155" at 57.635,67.539 h1.2
  text "0,254mm (10,00mil)" at 63.411,67.539 h1.2
  text "PTH" at 74.367,67.539 h1.2
  text "Round" at 79.313,67.539 h1.2
  text "Signal Layer 2 - Signal Layer 5" at 86.515,67.539 h1.2
  text "Via" at 102.598,67.539 h1.2
  text "G.   THROUGH VIA :" at -97.239,65.479 h3
  text "PLUG THE VIAS WHICH ARE COVERED WITH SOLDERMASK ONE OR TWO SIDE." at -58.739,65.479 h3
  text "155 Total" at 57.635,65.055 h1.2
  text "PLUG MATERIAL :" at -58.739,62.479 h3
  text "X  SOLDERMASK" at -33.239,62.479 h3
  text "NON-CONDUCTIVE EPOXY." at -7.989,62.479 h3
  text "Symbol" at 51.85,60.814 h1.44
  text "Count" at 57.485,60.814 h1.44
  text "Hole Size" at 63.346,60.814 h1.44
  text "Plated" at 74.302,60.814 h1.44
  text "Hole Type" at 79.249,60.814 h1.44
  text "Drill Layer Pair" at 86.45,60.814 h1.44
  text "Via/Pad" at 100.106,60.814 h1.44
  text "H.   STACK-UP :" at -97.239,59.479 h3
  text "SEE LAYER STACK-UP SEQUENCE FOR OVERALL THICKNESS." at -58.739,59.479 h3
  text "229" at 57.485,58.331 h1.2
  text "0,254mm (10,00mil)" at 63.346,58.331 h1.2
  text "PTH" at 74.302,58.331 h1.2
  text "Round" at 79.249,58.331 h1.2
  text "Top Layer - Bottom Layer" at 86.45,58.331 h1.2
  text "(Mixed)" at 100.106,58.331 h1.2
  text "3" at 57.485,55.847 h1.2
  text "0,800mm (31,50mil)" at 63.346,55.847 h1.2
  text "PTH" at 74.302,55.847 h1.2
  text "Round" at 79.249,55.847 h1.2
  text "Top Layer - Bottom Layer" at 86.45,55.847 h1.2
  text "Pad" at 100.106,55.847 h1.2
  text "4" at 57.485,53.364 h1.2
  text "0,991mm (39,00mil)" at 63.346,53.364 h1.2
  text "PTH" at 74.302,53.364 h1.2
  text "Round" at 79.249,53.364 h1.2
  text "Top Layer - Bottom Layer" at 86.45,53.364 h1.2
  text "Pad" at 100.106,53.364 h1.2
  text "1-8" at -78.22,52.17 h0.64 r90
  text "1-2" at -73.14,52.17 h0.64 r90
  text "*  SURFACE" at -34.005,51.897 h1.3
  text "236 Total" at 57.485,50.88 h1.2
  text "L1 Top Layer" at -34.005,50.688 h1.3
  text "*  Dielectric 1" at -34.005,47.573 h1.3
  text "Layer" at 51.492,45.475 h1.2
  text "Name" at 56.514,45.475 h1.2
  text "Material" at 66.225,45.475 h1.2
  text "Thickness" at 74.952,45.475 h1.2
  text "Constant" at 82.12,45.475 h1.2
  text "Board Layer Stack" at 88.755,45.475 h1.2
  text "2-3" at -68.06,45.16 h0.64 r90
  text "L2 Signal Layer 1" at -34.005,43.678 h1.3
  text "1" at 51.492,43.075 h1.2
  text "Top Overlay" at 56.514,43.075 h1.2
  text "2" at 51.492,40.675 h1.2
  text "Top Solder" at 56.514,40.675 h1.2
  text "Solder Resist" at 66.225,40.675 h1.2
  text "0,010mm" at 74.952,40.675 h1.2
  text "3,5" at 82.12,40.675 h1.2
  text "*  Dielectric 2" at -34.005,40.562 h1.3
  text "3" at 51.492,38.275 h1.2
  text "Top Layer" at 56.514,38.275 h1.2
  text "Copper" at 66.225,38.275 h1.2
  text "0,035mm" at 74.952,38.275 h1.2
  text "3-6" at -62.98,38.149 h0.64 r90
  text "L3 Signal Layer 2" at -34.005,36.668 h1.3
  text "4" at 51.492,35.875 h1.2
  text "Dielectric 1" at 56.514,35.875 h1.2
  text "0,074mm" at 74.952,35.875 h1.2
  text "4,5" at 82.12,35.875 h1.2
  text "*  Dielectric 3" at -34.005,33.552 h1.3
  text "5" at 51.492,33.475 h1.2
  text "Signal Layer 1" at 56.514,33.475 h1.2
  text "Copper" at 66.225,33.475 h1.2
  text "0,035mm" at 74.952,33.475 h1.2
  text "6" at 51.492,31.075 h1.2
  text "Dielectric 2" at 56.514,31.075 h1.2
  text "0,074mm" at 74.952,31.075 h1.2
  text "4,5" at 82.12,31.075 h1.2
  text "L4 Signal Layer 3" at -34.005,29.657 h1.3
  text "7" at 51.492,28.675 h1.2
  text "Signal Layer 2" at 56.514,28.675 h1.2
  text "Copper" at 66.225,28.675 h1.2
  text "0,035mm" at 74.952,28.675 h1.2
  text "*  Dielectric 4" at -34.005,26.541 h1.3
  text "8" at 51.492,26.275 h1.2
  text "Dielectric 3" at 56.514,26.275 h1.2
  text "0,180mm" at 74.952,26.275 h1.2
  text "4,5" at 82.12,26.275 h1.2
  text "9" at 51.492,23.875 h1.2
  text "Signal Layer 3" at 56.514,23.875 h1.2
  text "Copper" at 66.225,23.875 h1.2
  text "0,035mm" at 74.952,23.875 h1.2
  text "L5 Signal Layer 4" at -34.005,22.647 h1.3
  text "10" at 51.492,21.475 h1.2
  text "Dielectric 4" at 56.514,21.475 h1.2
  text "0,600mm" at 74.952,21.475 h1.2
  text "4,5" at 82.12,21.475 h1.2
  text "*  Dielectric 5" at -34.005,19.531 h1.3
  text "11" at 51.492,19.075 h1.2
  text "Signal Layer 4" at 56.514,19.075 h1.2
  text "Copper" at 66.225,19.075 h1.2
  text "0,035mm" at 74.952,19.075 h1.2
  text "INTERNAL CUTTING" at -17.625,18.075 h2
  text "6-7" at -57.9,17.118 h0.64 r90
  text "12" at 51.492,16.675 h1.2
  text "Dielectric 5" at 56.514,16.675 h1.2
  text "0,180mm" at 74.952,16.675 h1.2
  text "4,5" at 82.12,16.675 h1.2
  text "1mm" at -10.35,15.875 h2
  text "L6 Signal Layer 5" at -34.005,15.636 h1.3
  text "13" at 51.492,14.275 h1.2
  text "Signal Layer 5" at 56.514,14.275 h1.2
  text "Copper" at 66.225,14.275 h1.2
  text "0,035mm" at 74.952,14.275 h1.2
  text "*  Dielectric 6" at -34.005,12.521 h1.3
  text "14" at 51.492,11.875 h1.2
  text "Dielectric 6" at 56.514,11.875 h1.2
  text "0,074mm" at 74.952,11.875 h1.2
  text "4,5" at 82.12,11.875 h1.2
  text "7-8" at -52.82,10.108 h0.64 r90
  text "15" at 51.492,9.475 h1.2
  text "Signal Layer 6" at 56.514,9.475 h1.2
  text "Copper" at 66.225,9.475 h1.2
  text "0,035mm" at 74.952,9.475 h1.2
  text "L7 Signal Layer 6" at -34.005,8.626 h1.3
  text "16" at 51.492,7.075 h1.2
  text "Dielectric 7" at 56.514,7.075 h1.2
  text "0,074mm" at 74.952,7.075 h1.2
  text "4,5" at 82.12,7.075 h1.2
  text "*  Dielectric 7" at -34.005,5.51 h1.3
  text "17" at 51.492,4.675 h1.2
  text "Bottom Layer" at 56.514,4.675 h1.2
  text "Copper" at 66.225,4.675 h1.2
  text "0,035mm" at 74.952,4.675 h1.2
  text "18" at 51.492,2.275 h1.2
  text "Bottom Solder" at 56.514,2.275 h1.2
  text "Solder Resist" at 66.225,2.275 h1.2
  text "0,010mm" at 74.952,2.275 h1.2
  text "3,5" at 82.12,2.275 h1.2
  text "L8 Bottom Layer" at -34.005,1.616 h1.3
  text "*  SURFACE" at -34.005,0.526 h1.3
  text "19" at 51.492,-0.125 h1.2
  text "Bottom Overlay" at 56.514,-0.125 h1.2
  text "DESIGN CROSS SECTION CHART" at -66.409,-0.78 h1.3
  text "_____________________________" at -66.663,-1.011 h1.3
  text "TOTAL THICKNESS 1.55633mm" at -65.901,-2.283 h1.3
M20-Top Title Box:
  lines w0.025: 9.266,5.664 9.266,5.664

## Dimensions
0,41 to 12.239,41 on M2-Board Dimensions
13.25,0 to 31,0 on M2-Board Dimensions
31,0 to 31,41 on M2-Board Dimensions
